# Generated by FakeRAM 2.0
VERSION 5.7 ;
BUSBITCHARS "[]" ;
PROPERTYDEFINITIONS
  MACRO width INTEGER ;
  MACRO depth INTEGER ;
  MACRO banks INTEGER ;
END PROPERTYDEFINITIONS
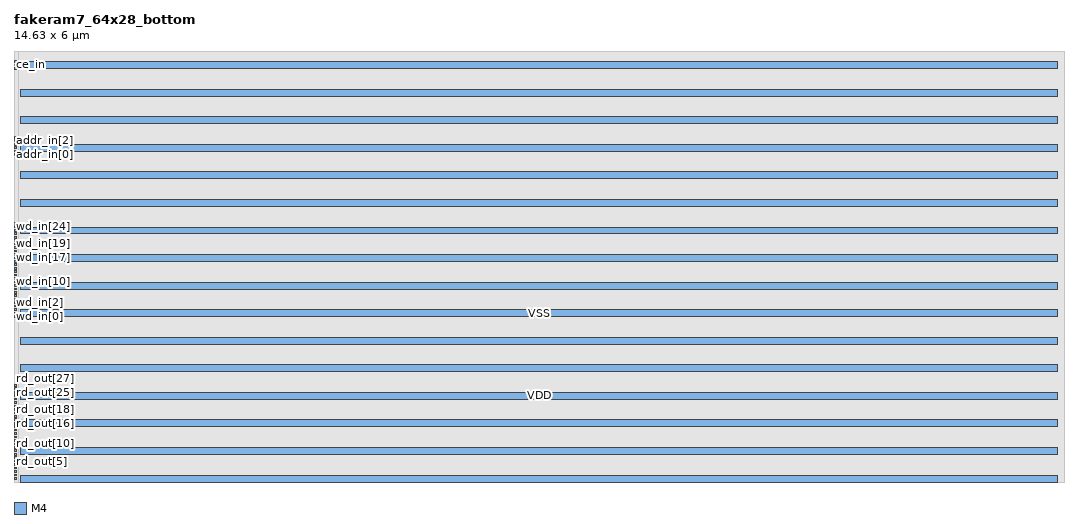
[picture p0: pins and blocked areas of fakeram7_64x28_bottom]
MACRO fakeram7_64x28_bottom
  PROPERTY width 28 ;
  PROPERTY depth 64 ;
  PROPERTY banks 4 ;
  FOREIGN fakeram7_64x28_bottom 0 0 ;
  SYMMETRY X Y R90 ;
  SIZE 14.630 BY 6.000 ;
  CLASS BLOCK ;
  PIN rd_out[0]
    DIRECTION OUTPUT ;
    USE SIGNAL ;
    SHAPE ABUTMENT ;
    PORT
      LAYER M4 ;
      RECT 0.000 0.039 0.036 0.063 ;
    END
  END rd_out[0]
  PIN rd_out[1]
    DIRECTION OUTPUT ;
    USE SIGNAL ;
    SHAPE ABUTMENT ;
    PORT
      LAYER M4 ;
      RECT 0.000 0.087 0.036 0.111 ;
    END
  END rd_out[1]
  PIN rd_out[2]
    DIRECTION OUTPUT ;
    USE SIGNAL ;
    SHAPE ABUTMENT ;
    PORT
      LAYER M4 ;
      RECT 0.000 0.135 0.036 0.159 ;
    END
  END rd_out[2]
  PIN rd_out[3]
    DIRECTION OUTPUT ;
    USE SIGNAL ;
    SHAPE ABUTMENT ;
    PORT
      LAYER M4 ;
      RECT 0.000 0.183 0.036 0.207 ;
    END
  END rd_out[3]
  PIN rd_out[4]
    DIRECTION OUTPUT ;
    USE SIGNAL ;
    SHAPE ABUTMENT ;
    PORT
      LAYER M4 ;
      RECT 0.000 0.231 0.036 0.255 ;
    END
  END rd_out[4]
  PIN rd_out[5]
    DIRECTION OUTPUT ;
    USE SIGNAL ;
    SHAPE ABUTMENT ;
    PORT
      LAYER M4 ;
      RECT 0.000 0.279 0.036 0.303 ;
    END
  END rd_out[5]
  PIN rd_out[6]
    DIRECTION OUTPUT ;
    USE SIGNAL ;
    SHAPE ABUTMENT ;
    PORT
      LAYER M4 ;
      RECT 0.000 0.327 0.036 0.351 ;
    END
  END rd_out[6]
  PIN rd_out[7]
    DIRECTION OUTPUT ;
    USE SIGNAL ;
    SHAPE ABUTMENT ;
    PORT
      LAYER M4 ;
      RECT 0.000 0.375 0.036 0.399 ;
    END
  END rd_out[7]
  PIN rd_out[8]
    DIRECTION OUTPUT ;
    USE SIGNAL ;
    SHAPE ABUTMENT ;
    PORT
      LAYER M4 ;
      RECT 0.000 0.423 0.036 0.447 ;
    END
  END rd_out[8]
  PIN rd_out[9]
    DIRECTION OUTPUT ;
    USE SIGNAL ;
    SHAPE ABUTMENT ;
    PORT
      LAYER M4 ;
      RECT 0.000 0.471 0.036 0.495 ;
    END
  END rd_out[9]
  PIN rd_out[10]
    DIRECTION OUTPUT ;
    USE SIGNAL ;
    SHAPE ABUTMENT ;
    PORT
      LAYER M4 ;
      RECT 0.000 0.519 0.036 0.543 ;
    END
  END rd_out[10]
  PIN rd_out[11]
    DIRECTION OUTPUT ;
    USE SIGNAL ;
    SHAPE ABUTMENT ;
    PORT
      LAYER M4 ;
      RECT 0.000 0.567 0.036 0.591 ;
    END
  END rd_out[11]
  PIN rd_out[12]
    DIRECTION OUTPUT ;
    USE SIGNAL ;
    SHAPE ABUTMENT ;
    PORT
      LAYER M4 ;
      RECT 0.000 0.615 0.036 0.639 ;
    END
  END rd_out[12]
  PIN rd_out[13]
    DIRECTION OUTPUT ;
    USE SIGNAL ;
    SHAPE ABUTMENT ;
    PORT
      LAYER M4 ;
      RECT 0.000 0.663 0.036 0.687 ;
    END
  END rd_out[13]
  PIN rd_out[14]
    DIRECTION OUTPUT ;
    USE SIGNAL ;
    SHAPE ABUTMENT ;
    PORT
      LAYER M4 ;
      RECT 0.000 0.711 0.036 0.735 ;
    END
  END rd_out[14]
  PIN rd_out[15]
    DIRECTION OUTPUT ;
    USE SIGNAL ;
    SHAPE ABUTMENT ;
    PORT
      LAYER M4 ;
      RECT 0.000 0.759 0.036 0.783 ;
    END
  END rd_out[15]
  PIN rd_out[16]
    DIRECTION OUTPUT ;
    USE SIGNAL ;
    SHAPE ABUTMENT ;
    PORT
      LAYER M4 ;
      RECT 0.000 0.807 0.036 0.831 ;
    END
  END rd_out[16]
  PIN rd_out[17]
    DIRECTION OUTPUT ;
    USE SIGNAL ;
    SHAPE ABUTMENT ;
    PORT
      LAYER M4 ;
      RECT 0.000 0.855 0.036 0.879 ;
    END
  END rd_out[17]
  PIN rd_out[18]
    DIRECTION OUTPUT ;
    USE SIGNAL ;
    SHAPE ABUTMENT ;
    PORT
      LAYER M4 ;
      RECT 0.000 0.903 0.036 0.927 ;
    END
  END rd_out[18]
  PIN rd_out[19]
    DIRECTION OUTPUT ;
    USE SIGNAL ;
    SHAPE ABUTMENT ;
    PORT
      LAYER M4 ;
      RECT 0.000 0.951 0.036 0.975 ;
    END
  END rd_out[19]
  PIN rd_out[20]
    DIRECTION OUTPUT ;
    USE SIGNAL ;
    SHAPE ABUTMENT ;
    PORT
      LAYER M4 ;
      RECT 0.000 0.999 0.036 1.023 ;
    END
  END rd_out[20]
  PIN rd_out[21]
    DIRECTION OUTPUT ;
    USE SIGNAL ;
    SHAPE ABUTMENT ;
    PORT
      LAYER M4 ;
      RECT 0.000 1.047 0.036 1.071 ;
    END
  END rd_out[21]
  PIN rd_out[22]
    DIRECTION OUTPUT ;
    USE SIGNAL ;
    SHAPE ABUTMENT ;
    PORT
      LAYER M4 ;
      RECT 0.000 1.095 0.036 1.119 ;
    END
  END rd_out[22]
  PIN rd_out[23]
    DIRECTION OUTPUT ;
    USE SIGNAL ;
    SHAPE ABUTMENT ;
    PORT
      LAYER M4 ;
      RECT 0.000 1.143 0.036 1.167 ;
    END
  END rd_out[23]
  PIN rd_out[24]
    DIRECTION OUTPUT ;
    USE SIGNAL ;
    SHAPE ABUTMENT ;
    PORT
      LAYER M4 ;
      RECT 0.000 1.191 0.036 1.215 ;
    END
  END rd_out[24]
  PIN rd_out[25]
    DIRECTION OUTPUT ;
    USE SIGNAL ;
    SHAPE ABUTMENT ;
    PORT
      LAYER M4 ;
      RECT 0.000 1.239 0.036 1.263 ;
    END
  END rd_out[25]
  PIN rd_out[26]
    DIRECTION OUTPUT ;
    USE SIGNAL ;
    SHAPE ABUTMENT ;
    PORT
      LAYER M4 ;
      RECT 0.000 1.287 0.036 1.311 ;
    END
  END rd_out[26]
  PIN rd_out[27]
    DIRECTION OUTPUT ;
    USE SIGNAL ;
    SHAPE ABUTMENT ;
    PORT
      LAYER M4 ;
      RECT 0.000 1.335 0.036 1.359 ;
    END
  END rd_out[27]
  PIN wd_in[0]
    DIRECTION INPUT ;
    USE SIGNAL ;
    SHAPE ABUTMENT ;
    PORT
      LAYER M4 ;
      RECT 0.000 2.295 0.036 2.319 ;
    END
  END wd_in[0]
  PIN wd_in[1]
    DIRECTION INPUT ;
    USE SIGNAL ;
    SHAPE ABUTMENT ;
    PORT
      LAYER M4 ;
      RECT 0.000 2.343 0.036 2.367 ;
    END
  END wd_in[1]
  PIN wd_in[2]
    DIRECTION INPUT ;
    USE SIGNAL ;
    SHAPE ABUTMENT ;
    PORT
      LAYER M4 ;
      RECT 0.000 2.391 0.036 2.415 ;
    END
  END wd_in[2]
  PIN wd_in[3]
    DIRECTION INPUT ;
    USE SIGNAL ;
    SHAPE ABUTMENT ;
    PORT
      LAYER M4 ;
      RECT 0.000 2.439 0.036 2.463 ;
    END
  END wd_in[3]
  PIN wd_in[4]
    DIRECTION INPUT ;
    USE SIGNAL ;
    SHAPE ABUTMENT ;
    PORT
      LAYER M4 ;
      RECT 0.000 2.487 0.036 2.511 ;
    END
  END wd_in[4]
  PIN wd_in[5]
    DIRECTION INPUT ;
    USE SIGNAL ;
    SHAPE ABUTMENT ;
    PORT
      LAYER M4 ;
      RECT 0.000 2.535 0.036 2.559 ;
    END
  END wd_in[5]
  PIN wd_in[6]
    DIRECTION INPUT ;
    USE SIGNAL ;
    SHAPE ABUTMENT ;
    PORT
      LAYER M4 ;
      RECT 0.000 2.583 0.036 2.607 ;
    END
  END wd_in[6]
  PIN wd_in[7]
    DIRECTION INPUT ;
    USE SIGNAL ;
    SHAPE ABUTMENT ;
    PORT
      LAYER M4 ;
      RECT 0.000 2.631 0.036 2.655 ;
    END
  END wd_in[7]
  PIN wd_in[8]
    DIRECTION INPUT ;
    USE SIGNAL ;
    SHAPE ABUTMENT ;
    PORT
      LAYER M4 ;
      RECT 0.000 2.679 0.036 2.703 ;
    END
  END wd_in[8]
  PIN wd_in[9]
    DIRECTION INPUT ;
    USE SIGNAL ;
    SHAPE ABUTMENT ;
    PORT
      LAYER M4 ;
      RECT 0.000 2.727 0.036 2.751 ;
    END
  END wd_in[9]
  PIN wd_in[10]
    DIRECTION INPUT ;
    USE SIGNAL ;
    SHAPE ABUTMENT ;
    PORT
      LAYER M4 ;
      RECT 0.000 2.775 0.036 2.799 ;
    END
  END wd_in[10]
  PIN wd_in[11]
    DIRECTION INPUT ;
    USE SIGNAL ;
    SHAPE ABUTMENT ;
    PORT
      LAYER M4 ;
      RECT 0.000 2.823 0.036 2.847 ;
    END
  END wd_in[11]
  PIN wd_in[12]
    DIRECTION INPUT ;
    USE SIGNAL ;
    SHAPE ABUTMENT ;
    PORT
      LAYER M4 ;
      RECT 0.000 2.871 0.036 2.895 ;
    END
  END wd_in[12]
  PIN wd_in[13]
    DIRECTION INPUT ;
    USE SIGNAL ;
    SHAPE ABUTMENT ;
    PORT
      LAYER M4 ;
      RECT 0.000 2.919 0.036 2.943 ;
    END
  END wd_in[13]
  PIN wd_in[14]
    DIRECTION INPUT ;
    USE SIGNAL ;
    SHAPE ABUTMENT ;
    PORT
      LAYER M4 ;
      RECT 0.000 2.967 0.036 2.991 ;
    END
  END wd_in[14]
  PIN wd_in[15]
    DIRECTION INPUT ;
    USE SIGNAL ;
    SHAPE ABUTMENT ;
    PORT
      LAYER M4 ;
      RECT 0.000 3.015 0.036 3.039 ;
    END
  END wd_in[15]
  PIN wd_in[16]
    DIRECTION INPUT ;
    USE SIGNAL ;
    SHAPE ABUTMENT ;
    PORT
      LAYER M4 ;
      RECT 0.000 3.063 0.036 3.087 ;
    END
  END wd_in[16]
  PIN wd_in[17]
    DIRECTION INPUT ;
    USE SIGNAL ;
    SHAPE ABUTMENT ;
    PORT
      LAYER M4 ;
      RECT 0.000 3.111 0.036 3.135 ;
    END
  END wd_in[17]
  PIN wd_in[18]
    DIRECTION INPUT ;
    USE SIGNAL ;
    SHAPE ABUTMENT ;
    PORT
      LAYER M4 ;
      RECT 0.000 3.159 0.036 3.183 ;
    END
  END wd_in[18]
  PIN wd_in[19]
    DIRECTION INPUT ;
    USE SIGNAL ;
    SHAPE ABUTMENT ;
    PORT
      LAYER M4 ;
      RECT 0.000 3.207 0.036 3.231 ;
    END
  END wd_in[19]
  PIN wd_in[20]
    DIRECTION INPUT ;
    USE SIGNAL ;
    SHAPE ABUTMENT ;
    PORT
      LAYER M4 ;
      RECT 0.000 3.255 0.036 3.279 ;
    END
  END wd_in[20]
  PIN wd_in[21]
    DIRECTION INPUT ;
    USE SIGNAL ;
    SHAPE ABUTMENT ;
    PORT
      LAYER M4 ;
      RECT 0.000 3.303 0.036 3.327 ;
    END
  END wd_in[21]
  PIN wd_in[22]
    DIRECTION INPUT ;
    USE SIGNAL ;
    SHAPE ABUTMENT ;
    PORT
      LAYER M4 ;
      RECT 0.000 3.351 0.036 3.375 ;
    END
  END wd_in[22]
  PIN wd_in[23]
    DIRECTION INPUT ;
    USE SIGNAL ;
    SHAPE ABUTMENT ;
    PORT
      LAYER M4 ;
      RECT 0.000 3.399 0.036 3.423 ;
    END
  END wd_in[23]
  PIN wd_in[24]
    DIRECTION INPUT ;
    USE SIGNAL ;
    SHAPE ABUTMENT ;
    PORT
      LAYER M4 ;
      RECT 0.000 3.447 0.036 3.471 ;
    END
  END wd_in[24]
  PIN wd_in[25]
    DIRECTION INPUT ;
    USE SIGNAL ;
    SHAPE ABUTMENT ;
    PORT
      LAYER M4 ;
      RECT 0.000 3.495 0.036 3.519 ;
    END
  END wd_in[25]
  PIN wd_in[26]
    DIRECTION INPUT ;
    USE SIGNAL ;
    SHAPE ABUTMENT ;
    PORT
      LAYER M4 ;
      RECT 0.000 3.543 0.036 3.567 ;
    END
  END wd_in[26]
  PIN wd_in[27]
    DIRECTION INPUT ;
    USE SIGNAL ;
    SHAPE ABUTMENT ;
    PORT
      LAYER M4 ;
      RECT 0.000 3.591 0.036 3.615 ;
    END
  END wd_in[27]
  PIN addr_in[0]
    DIRECTION INPUT ;
    USE SIGNAL ;
    SHAPE ABUTMENT ;
    PORT
      LAYER M4 ;
      RECT 0.000 4.551 0.036 4.575 ;
    END
  END addr_in[0]
  PIN addr_in[1]
    DIRECTION INPUT ;
    USE SIGNAL ;
    SHAPE ABUTMENT ;
    PORT
      LAYER M4 ;
      RECT 0.000 4.599 0.036 4.623 ;
    END
  END addr_in[1]
  PIN addr_in[2]
    DIRECTION INPUT ;
    USE SIGNAL ;
    SHAPE ABUTMENT ;
    PORT
      LAYER M4 ;
      RECT 0.000 4.647 0.036 4.671 ;
    END
  END addr_in[2]
  PIN addr_in[3]
    DIRECTION INPUT ;
    USE SIGNAL ;
    SHAPE ABUTMENT ;
    PORT
      LAYER M4 ;
      RECT 0.000 4.695 0.036 4.719 ;
    END
  END addr_in[3]
  PIN addr_in[4]
    DIRECTION INPUT ;
    USE SIGNAL ;
    SHAPE ABUTMENT ;
    PORT
      LAYER M4 ;
      RECT 0.000 4.743 0.036 4.767 ;
    END
  END addr_in[4]
  PIN addr_in[5]
    DIRECTION INPUT ;
    USE SIGNAL ;
    SHAPE ABUTMENT ;
    PORT
      LAYER M4 ;
      RECT 0.000 4.791 0.036 4.815 ;
    END
  END addr_in[5]
  PIN we_in
    DIRECTION INPUT ;
    USE SIGNAL ;
    SHAPE ABUTMENT ;
    PORT
      LAYER M4 ;
      RECT 0.000 5.751 0.036 5.775 ;
    END
  END we_in
  PIN ce_in
    DIRECTION INPUT ;
    USE SIGNAL ;
    SHAPE ABUTMENT ;
    PORT
      LAYER M4 ;
      RECT 0.000 5.799 0.036 5.823 ;
    END
  END ce_in
  PIN clk
    DIRECTION INPUT ;
    USE SIGNAL ;
    SHAPE ABUTMENT ;
    PORT
      LAYER M4 ;
      RECT 0.000 5.847 0.036 5.871 ;
    END
  END clk
  PIN VSS
    DIRECTION INOUT ;
    USE GROUND ;
    PORT
      LAYER M4 ;
      RECT 0.096 0.000 14.534 0.096 ;
      RECT 0.096 0.768 14.534 0.864 ;
      RECT 0.096 1.536 14.534 1.632 ;
      RECT 0.096 2.304 14.534 2.400 ;
      RECT 0.096 3.072 14.534 3.168 ;
      RECT 0.096 3.840 14.534 3.936 ;
      RECT 0.096 4.608 14.534 4.704 ;
      RECT 0.096 5.376 14.534 5.472 ;
    END
  END VSS
  PIN VDD
    DIRECTION INOUT ;
    USE POWER ;
    PORT
      LAYER M4 ;
      RECT 0.096 0.384 14.534 0.480 ;
      RECT 0.096 1.152 14.534 1.248 ;
      RECT 0.096 1.920 14.534 2.016 ;
      RECT 0.096 2.688 14.534 2.784 ;
      RECT 0.096 3.456 14.534 3.552 ;
      RECT 0.096 4.224 14.534 4.320 ;
      RECT 0.096 4.992 14.534 5.088 ;
      RECT 0.096 5.760 14.534 5.856 ;
    END
  END VDD
  OBS
    LAYER M1 ;
    RECT 0 0 14.630 6.000 ;
    LAYER M2 ;
    RECT 0 0 14.630 6.000 ;
    LAYER M3 ;
    RECT 0.059 0.000 14.630 6.000 ;
    LAYER M4 ;
    RECT 0.059 0.000 14.630 6.000 ;
  END
END fakeram7_64x28_bottom

END LIBRARY
